VERSION 5.8 ;
BUSBITCHARS "[]" ;
DIVIDERCHAR "/" ;
UNITS
    DATABASE MICRONS 1000 ;
END UNITS

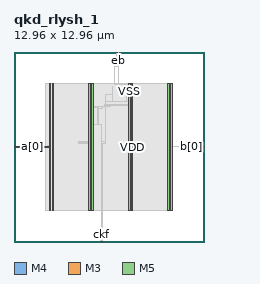
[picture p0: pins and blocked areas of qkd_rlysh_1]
MACRO qkd_rlysh_1
  FOREIGN qkd_rlysh_1 0 0 ;
  CLASS BLOCK ;
  SIZE 12.96 BY 12.96 ;
  PIN a[0]
    DIRECTION INPUT ;
    USE SIGNAL ;
    PORT
      LAYER M4 ;
        RECT  0 6.48 0.084 6.504 ;
    END
    PORT
      LAYER M4 ;
        RECT  0.06 6.48 2.408 6.504 ;
    END
  END a[0]
  PIN b[0]
    DIRECTION OUTPUT ;
    USE SIGNAL ;
    PORT
      LAYER M4 ;
        RECT  12.876 6.48 12.96 6.504 ;
    END
    PORT
      LAYER M4 ;
        RECT  12.841 6.48 12.924 6.504 ;
    END
  END b[0]
  PIN ck_o
    DIRECTION OUTPUT ;
    USE SIGNAL ;
    PORT
      LAYER M3 ;
        RECT  7.02 12.923 7.038 12.96 ;
    END
  END ck_o
  PIN ckf
    DIRECTION INPUT ;
    USE SIGNAL ;
    PORT
      LAYER M3 ;
        RECT  5.94 0 5.958 0.037 ;
    END
  END ckf
  PIN ea
    DIRECTION INPUT ;
    USE SIGNAL ;
    PORT
      LAYER M3 ;
        RECT  6.048 0 6.066 0.037 ;
    END
  END ea
  PIN eb
    DIRECTION OUTPUT ;
    USE SIGNAL ;
    PORT
      LAYER M3 ;
        RECT  7.128 12.923 7.146 12.96 ;
    END
  END eb
  PIN VDD
    DIRECTION INOUT ;
    USE POWER ;
    PORT
      LAYER M5 ;
        RECT  10.692 2.151 10.812 10.809 ;
        RECT  7.992 2.151 8.112 10.809 ;
        RECT  5.292 2.151 5.412 10.809 ;
        RECT  2.592 2.151 2.712 10.809 ;
    END
  END VDD
  PIN VSS
    DIRECTION INOUT ;
    USE GROUND ;
    PORT
      LAYER M5 ;
        RECT  10.5 2.137 10.62 10.823 ;
        RECT  7.8 2.137 7.92 10.823 ;
        RECT  5.1 2.137 5.22 10.823 ;
        RECT  2.4 2.137 2.52 10.823 ;
    END
  END VSS
  # OT_OBS_CLOSED layer=M5 d_um=1.536 added=1
  OBS
    LAYER RVTN ;
     RECT  2.16 2.16 10.8 2.295 ;
     RECT  2.16 2.565 10.8 2.835 ;
     RECT  2.16 3.105 10.8 3.375 ;
     RECT  2.16 3.645 10.8 3.915 ;
     RECT  2.16 4.185 10.8 4.455 ;
     RECT  2.16 4.725 10.8 4.995 ;
     RECT  2.16 5.265 10.8 5.535 ;
     RECT  2.16 5.805 10.8 6.075 ;
     RECT  2.16 6.345 10.8 6.615 ;
     RECT  2.16 6.885 10.8 7.155 ;
     RECT  2.16 7.425 10.8 7.695 ;
     RECT  2.16 7.965 10.8 8.235 ;
     RECT  2.16 8.505 10.8 8.775 ;
     RECT  2.16 9.045 10.8 9.315 ;
     RECT  2.16 9.585 10.8 9.855 ;
     RECT  2.16 10.125 10.8 10.395 ;
     RECT  2.16 10.665 10.8 10.8 ;
    LAYER RVTP ;
     RECT  2.16 2.295 10.8 2.565 ;
     RECT  2.16 2.835 10.8 3.105 ;
     RECT  2.16 3.375 10.8 3.645 ;
     RECT  2.16 3.915 10.8 4.185 ;
     RECT  2.16 4.455 10.8 4.725 ;
     RECT  2.16 4.995 10.8 5.265 ;
     RECT  2.16 5.535 10.8 5.805 ;
     RECT  2.16 6.075 10.8 6.345 ;
     RECT  2.16 6.615 10.8 6.885 ;
     RECT  2.16 7.155 10.8 7.425 ;
     RECT  2.16 7.695 10.8 7.965 ;
     RECT  2.16 8.235 10.8 8.505 ;
     RECT  2.16 8.775 10.8 9.045 ;
     RECT  2.16 9.315 10.8 9.585 ;
     RECT  2.16 9.855 10.8 10.125 ;
     RECT  2.16 10.395 10.8 10.665 ;
    LAYER M1 ;
     RECT  2.16 2.151 10.8 10.809 ;
    LAYER M2 ;
     RECT  2.16 2.151 10.8 10.809 ;
     RECT  10.8 2.421 10.812 10.539 ;
     RECT  10.812 6.516 12.875 6.534 ;
    LAYER M3 ;
     RECT  5.958 0.012 6.048 0.037 ;
     RECT  5.94 0.037 6.066 0.125 ;
     RECT  2.415 2.143 2.505 2.413 ;
     RECT  5.115 2.143 5.205 2.413 ;
     RECT  6.048 0.125 6.066 2.413 ;
     RECT  7.815 2.143 7.905 2.413 ;
     RECT  10.515 2.143 10.605 2.413 ;
     RECT  2.415 2.413 2.697 6.475 ;
     RECT  12.852 6.475 12.87 6.539 ;
     RECT  2.304 6.475 2.697 6.575 ;
     RECT  5.115 2.413 6.066 6.691 ;
     RECT  4.428 6.691 6.21 6.845 ;
     RECT  5.115 6.845 6.21 9.211 ;
     RECT  5.115 9.211 6.57 9.275 ;
     RECT  6.192 9.275 6.57 9.319 ;
     RECT  7.815 2.413 8.097 9.319 ;
     RECT  6.192 9.319 8.097 9.347 ;
     RECT  6.264 9.347 8.097 9.581 ;
     RECT  6.264 9.581 6.75 10.049 ;
     RECT  2.415 6.575 2.697 10.547 ;
     RECT  5.115 9.275 5.397 10.547 ;
     RECT  7.704 9.581 8.097 10.547 ;
     RECT  10.515 2.413 10.797 10.547 ;
     RECT  6.732 10.049 6.75 10.625 ;
     RECT  7.704 10.547 7.905 10.741 ;
     RECT  2.415 10.547 2.505 10.817 ;
     RECT  5.115 10.547 5.205 10.817 ;
     RECT  6.876 10.741 7.905 10.817 ;
     RECT  10.515 10.547 10.605 10.817 ;
     RECT  6.876 10.817 7.146 10.829 ;
     RECT  7.128 10.829 7.146 11.995 ;
     RECT  7.02 11.995 7.146 12.923 ;
     RECT  7.038 12.923 7.128 12.941 ;
    LAYER M4 ;
     RECT  2.408 2.148 2.512 10.812 ;
     RECT  2.512 2.418 2.704 10.542 ;
     RECT  4.417 6.816 5.108 6.84 ;
     RECT  5.108 2.148 5.212 10.812 ;
     RECT  5.212 2.418 5.404 10.542 ;
     RECT  5.404 6.816 5.501 9.24 ;
     RECT  5.501 7.296 5.645 9.24 ;
     RECT  5.645 7.392 5.699 9.24 ;
     RECT  5.699 7.968 5.74 9.24 ;
     RECT  5.9 0.096 5.987 0.12 ;
     RECT  5.74 7.968 5.987 7.992 ;
     RECT  5.74 9.12 6.041 9.24 ;
     RECT  6.041 9.216 6.581 9.24 ;
     RECT  6.853 10.8 6.94 10.824 ;
     RECT  6.853 12 7.049 12.024 ;
     RECT  6.94 10.8 7.808 10.812 ;
     RECT  7.808 2.148 7.912 10.812 ;
     RECT  7.912 2.418 8.104 10.542 ;
     RECT  10.508 2.148 10.612 10.812 ;
     RECT  10.612 2.418 10.804 10.542 ;
    LAYER M5 ;
     RECT  5.952 0.085 5.976 2.137 ;
     RECT  2.4 2.137 2.52 2.151 ;
     RECT  7.8 2.137 7.92 2.151 ;
     RECT  10.5 2.137 10.62 2.151 ;
     RECT  5.1 2.137 5.976 8.003 ;
     RECT  5.1 8.003 5.688 9.155 ;
     RECT  5.1 9.155 5.592 9.251 ;
     RECT  7.8 2.151 8.112 10.789 ;
     RECT  2.4 2.151 2.712 10.809 ;
     RECT  5.1 9.251 5.412 10.809 ;
     RECT  6.864 10.789 8.112 10.809 ;
     RECT  10.5 2.151 10.812 10.809 ;
     RECT  2.4 10.809 2.52 10.823 ;
     RECT  5.1 10.809 5.22 10.823 ;
     RECT  6.864 10.809 7.92 10.823 ;
     RECT  10.5 10.809 10.62 10.823 ;
     RECT  6.864 10.823 6.888 12.035 ;
     RECT  5.412 10.789 6.864 10.809 ;
  END
END qkd_rlysh_1
END LIBRARY
